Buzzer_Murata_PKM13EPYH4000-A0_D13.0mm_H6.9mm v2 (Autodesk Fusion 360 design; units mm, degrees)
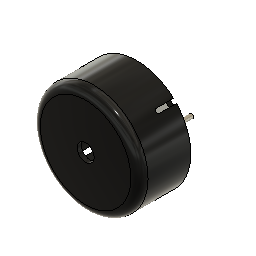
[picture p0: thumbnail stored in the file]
named bodies: "outer", "inner", "pin1", "pin2"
